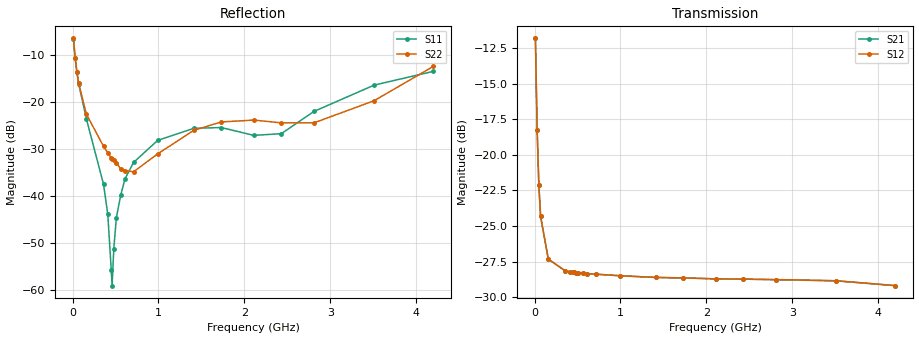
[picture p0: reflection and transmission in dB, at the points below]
! Integrated Device Technology
! Corporate Headquarters
! 6024 Silver Creek Valley Road
! San Jose, CA 95138  USA
! Phone:  1-408-284-8200
! Toll Free:  1-800-223-1366
! Webpage:  http://www.idt.com/
! Timing and RF Division
! 515 Groton Road, Suite 102
! Westford, MA 01886-6024
! Device:  F1950
! Description: 7-bit 0.25 dB Digital Step Attenuator
! Frequency:  150.0 -  4000.00 MHz
! Package:  4x4 mm Thin QFN Plastic Package: 24 pin
! Ports:  2 RF, 12 DC
!  Pin  1  = D0
!  Pin  2  = VDD
!  Pin  3  = Vmode
!  Pin  4  = GND
!  Pin  5  = RF1  =  Port 1
!  Pin  6  = GND
!  Pin  7  = GND
!  Pin  8  = GND
!  Pin  9  = GND
!  Pin 10  = GND
!  Pin 11  = GND
!  Pin 12  = GND
!  Pin 13  = GND
!  Pin 14  = RF2  =  Port 2
!  Pin 15  = GND
!  Pin 16  = LE
!  Pin 17  = CLK
!  Pin 18  = DATE
!  Pin 19  = D6
!  Pin 20  = D5
!  Pin 21  = D4
!  Pin 22  = D3
!  Pin 23  = D2
!  Pin 24  = D1
! State:  110
! Atten State:  27.50 dB
! Voltage:  +5.00 Volts
! Current:  Not Measured mA
! Data:  The device was measured on a the F195X evaluation board which has
!  individual transmission lines to the RF pins.  Data was collected
!  using a calibrated network analyzer.  The evaluation board was
!  de-embedded using a TRL calibration technique.
!  The reference plane is the edge of the package pin.
! Misc:  Board 2019
!  Action Tracker AT0250
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# GHz S dB R 50
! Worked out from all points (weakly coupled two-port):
!   420 points, 10 MHz to 4.2 GHz, reference 50 ohm
!   highest |S21| = -11.81 dB at 10 MHz (marker M1); lowest = -29.2 dB at 4.2 GHz (marker M2)
!   lowest |S11| = -59.0 dB at 460 MHz (marker M3), VSWR 1.00, Z = 49.9 - j0.048 ohm
!   |S11| at or under -10 dB: 26.28 MHz to end of sweep
!   |S22| runs from -35.1 to -6.5 dB; largest |S21 - S12| = 8.2e-05
!   S11 on the Smith chart (normalised r, x): 10 MHz: 1.97, -1.11; 30 MHz: 1.29, -0.63; 70 MHz: 1.09, -0.32; 450 MHz: 1.00, -0.00; 4.2 GHz: 0.69, +0.17
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0.01  -6.64 -28.4  -11.81 -39.5  -11.81 -39.5  -6.54 -29.4
0.03  -10.69 -50.1  -18.25 -56.5  -18.25 -56.5  -10.62 -51.7
0.05  -13.75 -60.0  -22.12 -54.1  -22.12 -54.1  -13.59 -61.8
0.07  -16.13 -65.6  -24.31 -47.6  -24.31 -47.6  -15.98 -66.9
0.16  -23.57 -71.8  -27.32 -27.8  -27.32 -27.8  -22.60 -75.6
0.36  -37.46 -67.7  -28.16 -16.3  -28.16 -16.3  -29.42 -85.6
0.41  -43.89 -73.5  -28.21 -15.4  -28.21 -15.4  -30.83 -87.8
0.45  -55.59 -105.2  -28.25 -14.8  -28.25 -14.8  -31.87 -93.5
0.46  -59.00 -154.6  -28.26 -14.7  -28.26 -14.7  -32.06 -95.2
0.48  -51.12 144.0  -28.27 -14.5  -28.27 -14.5  -32.37 -98.2
0.51  -44.55 136.7  -28.29 -14.3  -28.29 -14.3  -32.89 -100.9
0.56  -39.84 133.1  -28.31 -14.1  -28.31 -14.1  -34.27 -108.8
0.61  -36.33 134.8  -28.34 -14.0  -28.34 -14.0  -34.57 -119.9
0.71  -32.86 136.6  -28.38 -14.0  -28.38 -14.0  -34.84 -139.6
0.99  -28.18 146.5  -28.49 -15.1  -28.49 -15.1  -31.05 179.9
1.41  -25.63 162.2  -28.61 -17.5  -28.61 -17.6  -26.06 160.4
1.73  -25.45 167.4  -28.65 -19.7  -28.64 -19.7  -24.27 152.0
2.11  -27.12 156.7  -28.71 -23.0  -28.71 -23.0  -23.87 142.1
2.43  -26.75 124.8  -28.73 -25.3  -28.73 -25.3  -24.46 131.3
2.81  -22.04 104.4  -28.77 -28.8  -28.76 -28.8  -24.46 115.9
3.51  -16.46 116.8  -28.85 -34.5  -28.84 -34.6  -19.77 113.2
4.2  -13.54 145.3  -29.19 -37.9  -29.18 -38.0  -12.48 127.2
